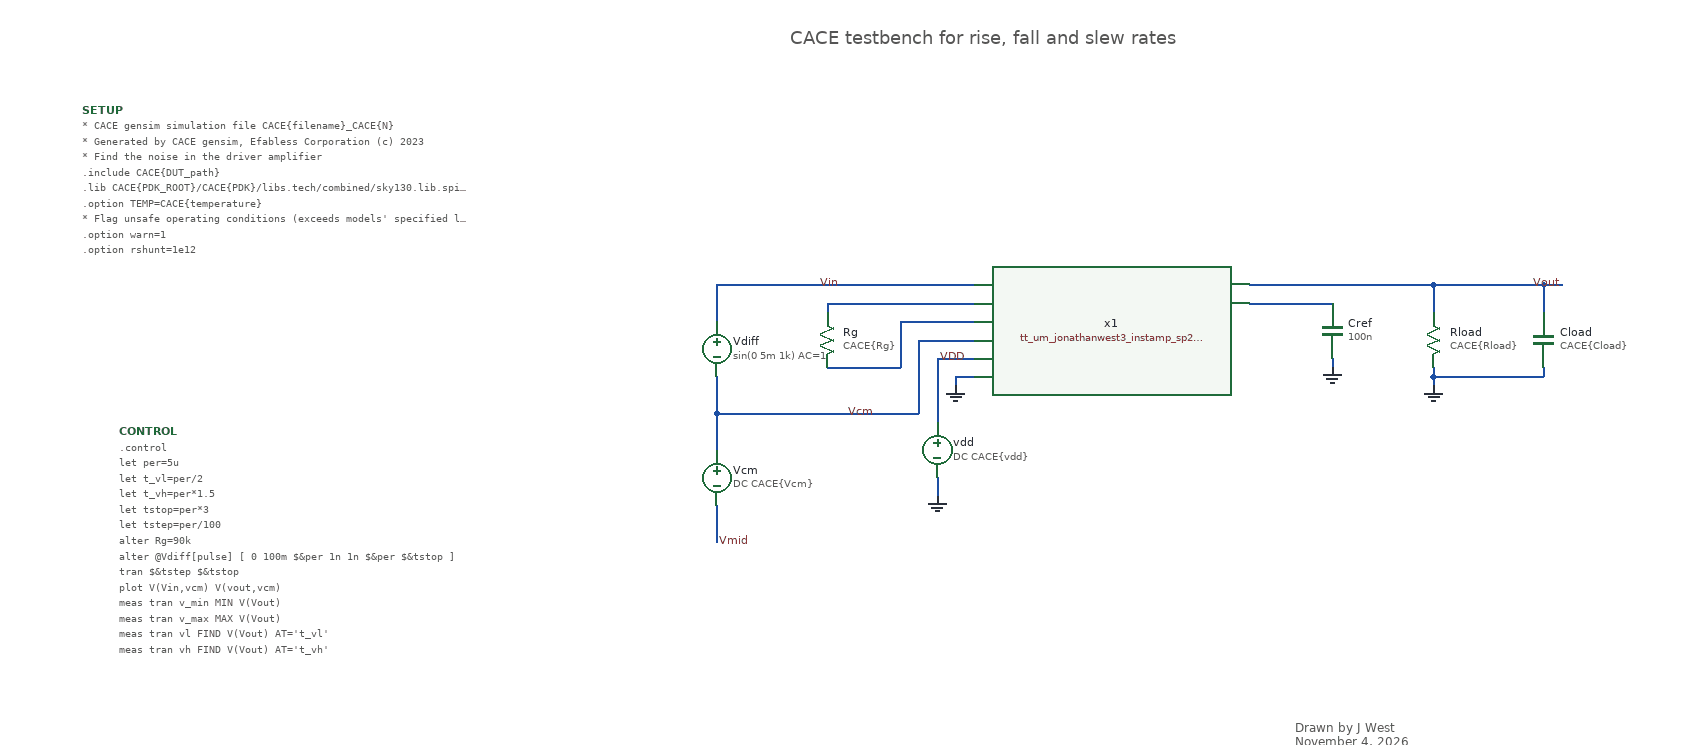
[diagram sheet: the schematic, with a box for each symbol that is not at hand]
v {xschem version=3.4.8RC file_version=1.3}
G {}
K {}
V {}
S {}
F {}
E {}
T {CACE testbench for rise, fall and slew rates} -390 -640 0 0 0.6 0.6 {}
T {Drawn by J West
November 4, 2026
Revision 0
} 160 110 0 0 0.4 0.4 {}
N 430 -360 450 -360 {
lab=Vout}
N -350 -340 -350 -330 {lab=#net1}
N -350 -340 -190 -340 {lab=#net1}
N -350 -270 -270 -270 {lab=#net2}
N -270 -300 -270 -270 {lab=#net2}
N -250 -280 -250 -220 {lab=Vcm}
N -470 -220 -250 -220 {lab=Vcm}
N 110 -340 200 -340 {lab=#net3}
N 200 -280 200 -270 {lab=GND}
N -230 -150 -230 -130 {lab=GND}
N -230 -230 -230 -210 {lab=VDD}
N -470 -120 -470 -110 {lab=Vmid}
N -470 -360 -190 -360 {lab=Vin}
N -230 -280 -190 -280 {lab=VDD}
N 310 -260 310 -250 {lab=GND}
N 310 -270 310 -260 {lab=GND}
N 360 -260 430 -260 {lab=GND}
N 430 -270 430 -260 {lab=GND}
N 430 -360 430 -330 {lab=Vout}
N 310 -360 310 -330 {lab=Vout}
N -470 -360 -470 -320 {lab=Vin}
N -470 -260 -470 -220 {lab=Vcm}
N -470 -220 -470 -180 {lab=Vcm}
N 360 -360 430 -360 {
lab=Vout}
N 110 -360 310 -360 {
lab=Vout}
N -230 -280 -230 -230 {lab=VDD}
N 310 -360 360 -360 {lab=Vout}
N 310 -260 360 -260 {lab=GND}
N -470 -110 -470 -80 {lab=Vmid}
N -270 -320 -270 -300 {lab=#net2}
N -270 -320 -190 -320 {lab=#net2}
N -250 -300 -250 -280 {lab=Vcm}
N -250 -300 -190 -300 {lab=Vcm}
N -210 -260 -210 -250 {lab=GND}
N -210 -260 -190 -260 {lab=GND}
C {devices/code_shown.sym} -1120 -200 0 0 {name=CONTROL only_toplevel=false value=".control
let per=5u
let t_vl=per/2
let t_vh=per*1.5
let tstop=per*3
let tstep=per/100
alter Rg=90k
alter @Vdiff[pulse] [ 0 100m $&per 1n 1n $&per $&tstop ] 
tran $&tstep $&tstop
plot V(Vin,vcm) V(vout,vcm)
meas tran v_min MIN V(Vout)
meas tran v_max MAX V(Vout)
meas tran vl FIND V(Vout) AT='t_vl'
meas tran vh FIND V(Vout) AT='t_vh'
meas tran v_pp PP V(Vout)
let v_high=(0.9*v_pp)+v_min
let v_low=(0.1*v_pp)+v_min
meas tran rise_time TRIG v(Vout) VAL='v_low' rise=1 targ v(vout) Val='v_high' RISE=1
meas tran fall_time TRIG v(Vout) VAL='v_high' fall=1 targ v(vout) Val='v_low' FALL=1
let sr_rise=(v_high-v_low)/rise_time
let sr_fall=(v_high-v_low)/fall_time
let over=v_max-vh
let under=vl-v_min
let sup_current = -i(Vdd)
meas tran ivdd AVG sup_current from=0 to='per' 

set gnuplot_terminal=png/quit
gnuplot v_rise_fall V(vin,vcm) V(Vout,vcm)
+ title 'Rise and Fall Times'
+ xlabel 'Time (s)' ylabel 'Volts'

echo $&rise_time $&fall_time $&sr_rise $&sr_fall $&over $&under $&ivdd> CACE\{simpath\}/CACE\{filename\}_CACE\{N\}.data

quit
.endc
"}
C {devices/code_shown.sym} -1160 -550 0 0 {name=SETUP only_toplevel=false value="* CACE gensim simulation file CACE\{filename\}_CACE\{N\}
* Generated by CACE gensim, Efabless Corporation (c) 2023
* Find the noise in the driver amplifier

.include CACE\{DUT_path\}

.lib CACE\{PDK_ROOT\}/CACE\{PDK\}/libs.tech/combined/sky130.lib.spice CACE\{corner\}

.option TEMP=CACE\{temperature\}
* Flag unsafe operating conditions (exceeds models' specified limits)
.option warn=1
.option rshunt=1e12
"}
C {devices/vsource.sym} -470 -150 0 0 {name=Vcm value="DC CACE\{Vcm\}" savecurrent=false}
C {devices/lab_wire.sym} 450 -360 0 0 {name=p25 sig_type=std_logic lab=Vout}
C {devices/vsource.sym} -230 -180 0 0 {name=vdd value="DC CACE\{vdd\}" savecurrent=false}
C {devices/lab_wire.sym} -330 -220 0 1 {name=p4 sig_type=std_logic lab=Vcm}
C {devices/res.sym} -350 -300 0 0 {name=Rg
value=CACE\{Rg\}
device=resistor}
C {capa.sym} 200 -310 0 0 {name=Cref
m=1
value=100n
footprint=1206
device="ceramic capacitor"}
C {devices/gnd.sym} 200 -270 0 0 {name=l2 lab=GND}
C {devices/gnd.sym} -230 -130 0 0 {name=l1 lab=GND}
C {devices/gnd.sym} -210 -250 0 0 {name=l5 lab=GND}
C {devices/lab_wire.sym} -230 -280 0 1 {name=p5 sig_type=std_logic lab=VDD}
C {devices/lab_wire.sym} -360 -360 0 1 {name=p6 sig_type=std_logic lab=Vin}
C {devices/res.sym} 310 -300 0 0 {name=Rload
value=CACE\{Rload\}
device=resistor}
C {capa.sym} 430 -300 0 0 {name=Cload
m=1
value=CACE\{Cload\}
footprint=1206
device="ceramic capacitor"}
C {devices/gnd.sym} 310 -250 0 0 {name=l3 lab=GND}
C {vsource.sym} -470 -290 0 0 {name=Vdiff value="sin(0 5m 1k) AC=1"}
C {devices/lab_wire.sym} -470 -80 0 1 {name=p2 sig_type=std_logic lab=Vmid}
C {tt_um_jonathanwest3_instamp_sp2026.sym} -40 -110 0 0 {name=x1}
